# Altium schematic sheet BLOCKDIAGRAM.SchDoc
size 420 x 297 mm

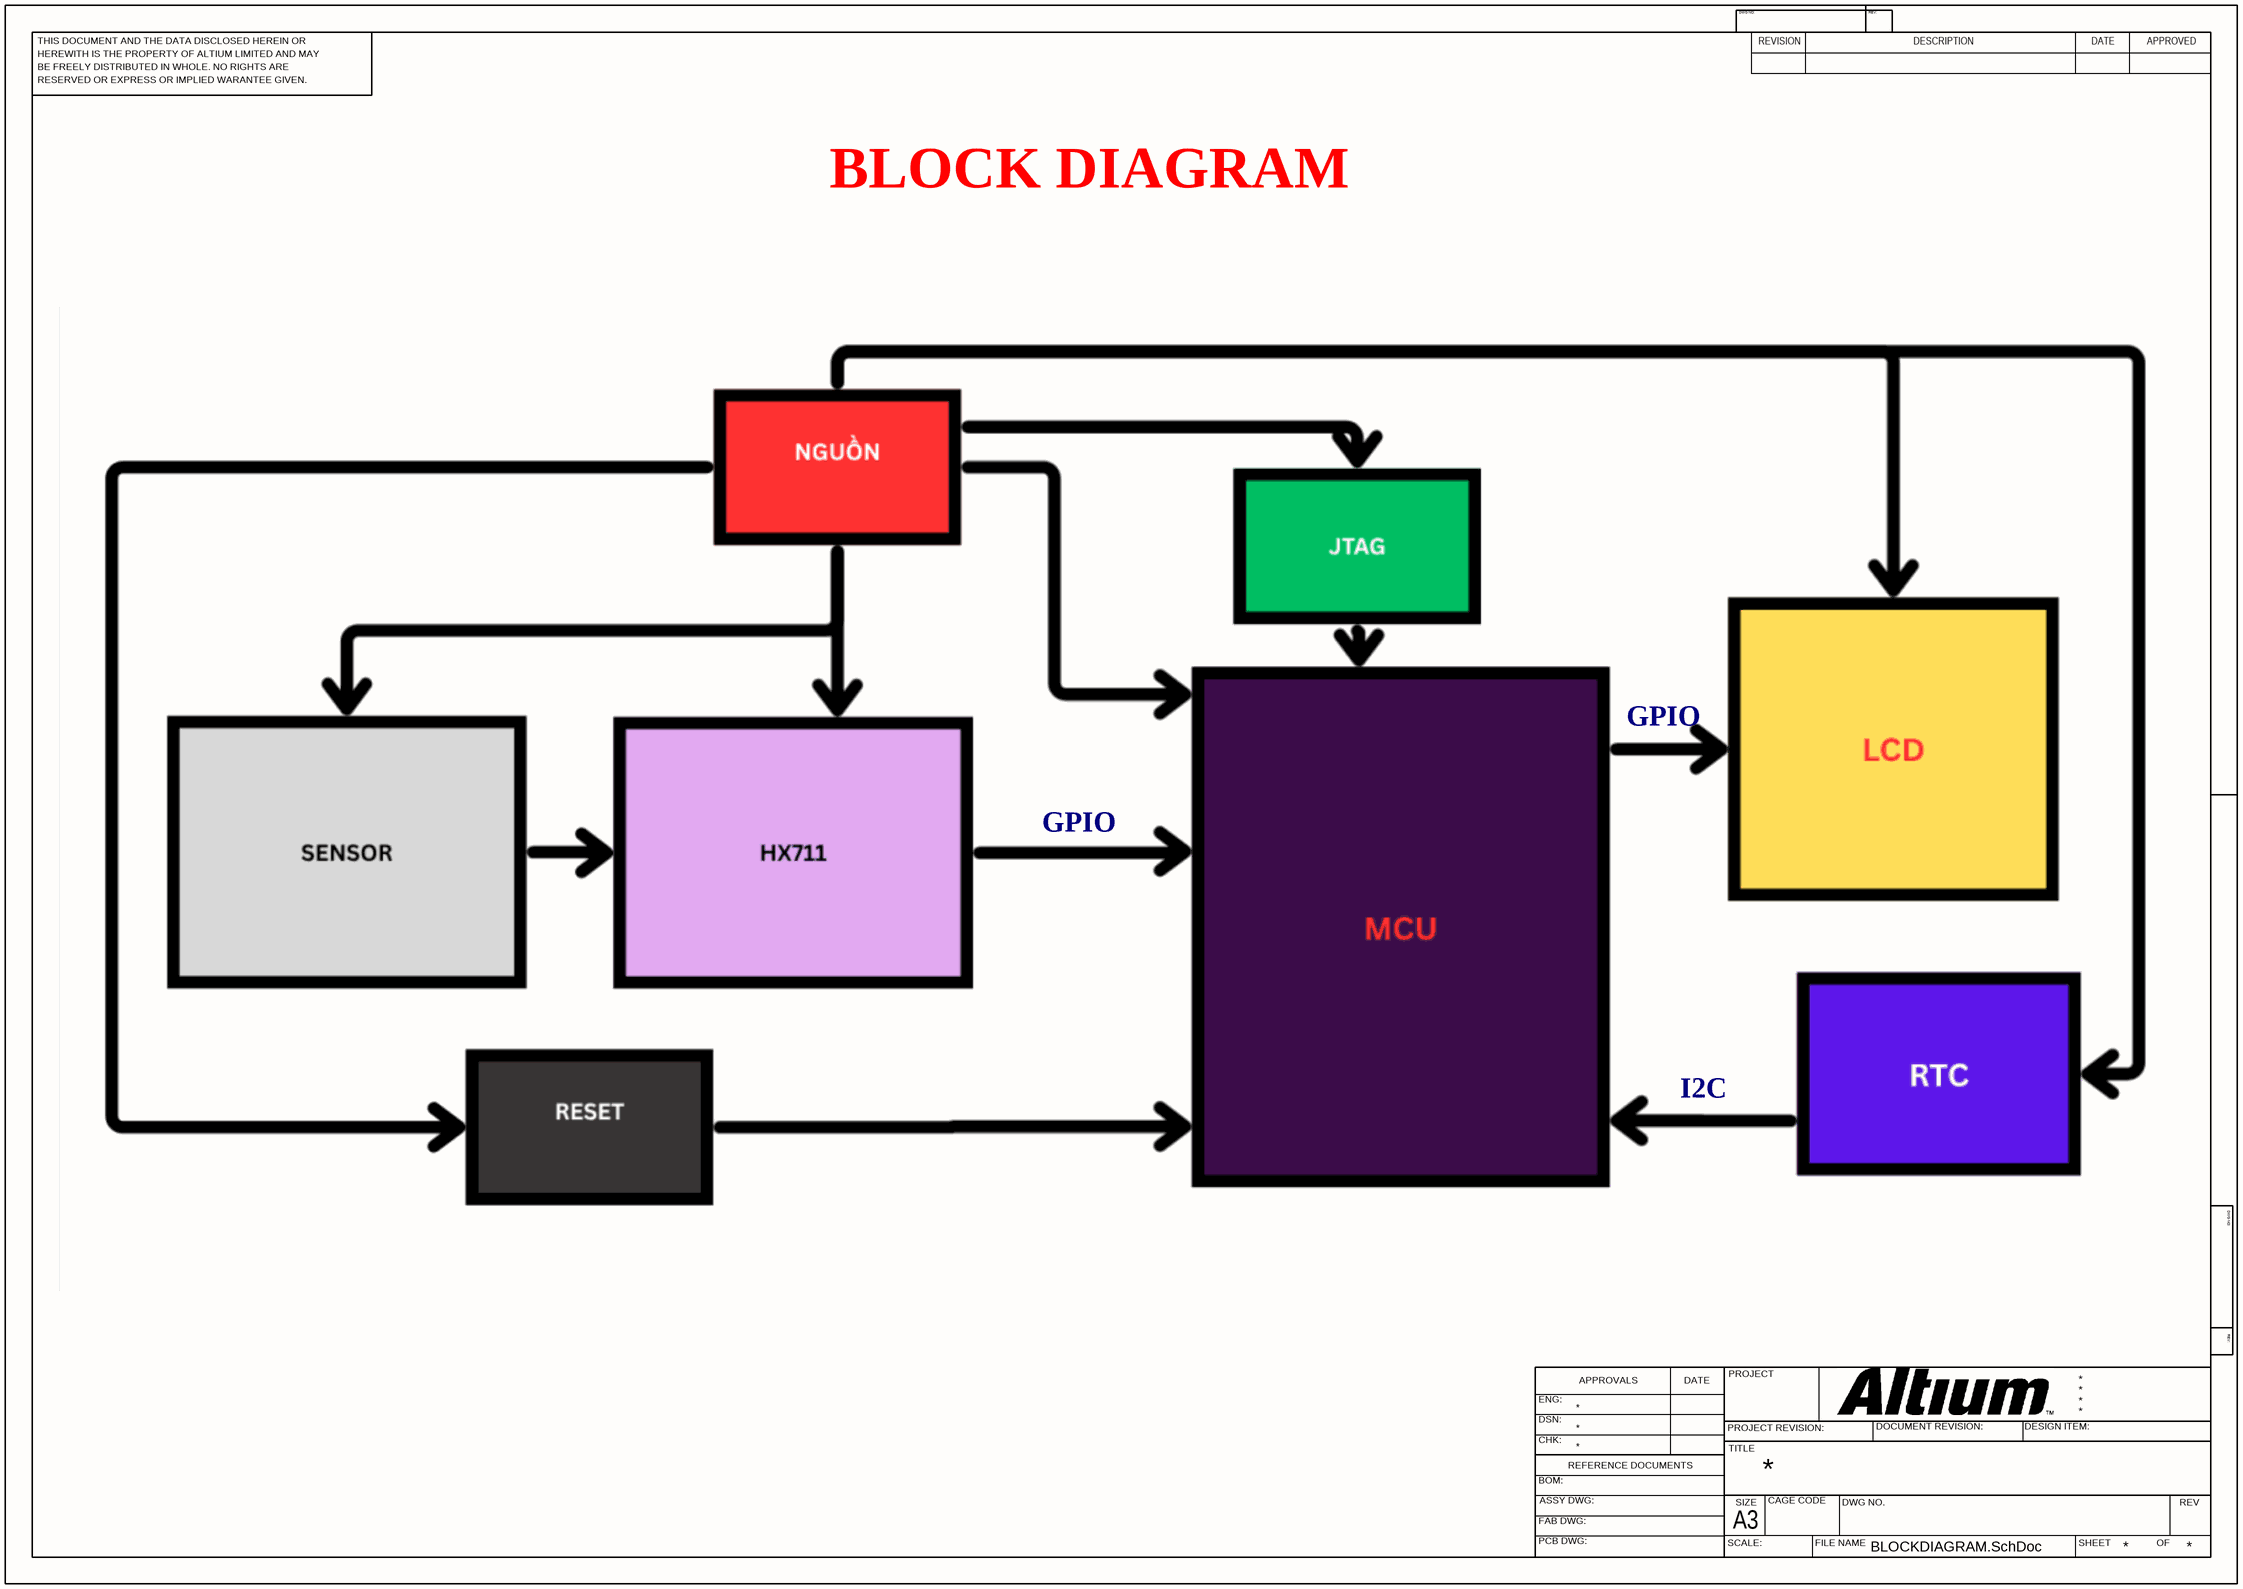
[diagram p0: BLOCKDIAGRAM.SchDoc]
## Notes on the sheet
- BLOCK DIAGRAM
- GPIO
- I2C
